VERSION 5.7 ;
  NOWIREEXTENSIONATPIN ON ;
  DIVIDERCHAR "/" ;
  BUSBITCHARS "[]" ;
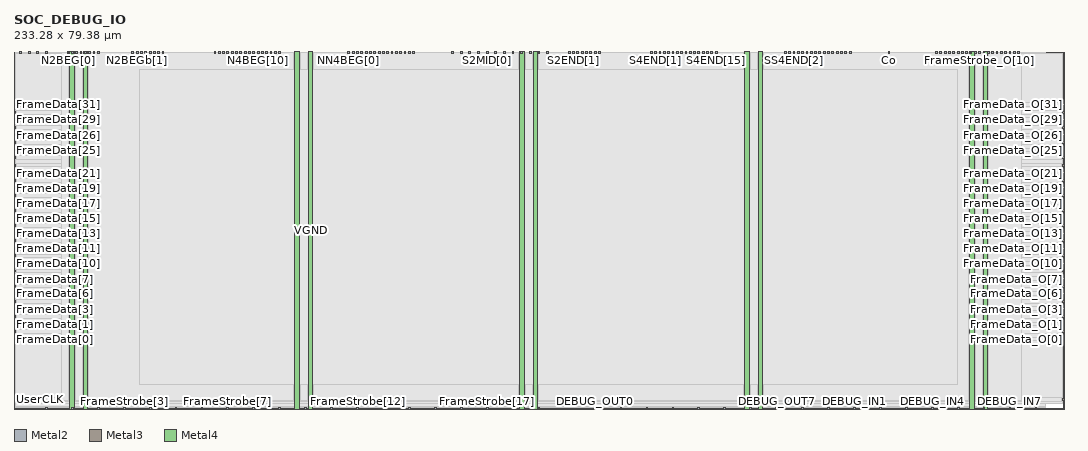
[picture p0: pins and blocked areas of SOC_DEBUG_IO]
MACRO SOC_DEBUG_IO
  CLASS BLOCK ;
  FOREIGN SOC_DEBUG_IO ;
  ORIGIN 0.000 0.000 ;
  SIZE 233.280 BY 79.380 ;
  PIN Co
    DIRECTION OUTPUT ;
    USE SIGNAL ;
    ANTENNADIFFAREA 2.314600 ;
    PORT
      LAYER Metal2 ;
        RECT 194.200 78.980 194.600 79.380 ;
    END
  END Co
  PIN DEBUG_IN0
    DIRECTION OUTPUT ;
    USE SIGNAL ;
    ANTENNADIFFAREA 2.647800 ;
    PORT
      LAYER Metal2 ;
        RECT 180.760 0.000 181.160 0.400 ;
    END
  END DEBUG_IN0
  PIN DEBUG_IN1
    DIRECTION OUTPUT ;
    USE SIGNAL ;
    ANTENNADIFFAREA 2.647800 ;
    PORT
      LAYER Metal2 ;
        RECT 186.520 0.000 186.920 0.400 ;
    END
  END DEBUG_IN1
  PIN DEBUG_IN2
    DIRECTION OUTPUT ;
    USE SIGNAL ;
    ANTENNADIFFAREA 2.647800 ;
    PORT
      LAYER Metal2 ;
        RECT 192.280 0.000 192.680 0.400 ;
    END
  END DEBUG_IN2
  PIN DEBUG_IN3
    DIRECTION OUTPUT ;
    USE SIGNAL ;
    ANTENNADIFFAREA 2.647800 ;
    PORT
      LAYER Metal2 ;
        RECT 198.040 0.000 198.440 0.400 ;
    END
  END DEBUG_IN3
  PIN DEBUG_IN4
    DIRECTION OUTPUT ;
    USE SIGNAL ;
    ANTENNADIFFAREA 2.647800 ;
    PORT
      LAYER Metal2 ;
        RECT 203.800 0.000 204.200 0.400 ;
    END
  END DEBUG_IN4
  PIN DEBUG_IN5
    DIRECTION OUTPUT ;
    USE SIGNAL ;
    ANTENNADIFFAREA 2.647800 ;
    PORT
      LAYER Metal2 ;
        RECT 209.560 0.000 209.960 0.400 ;
    END
  END DEBUG_IN5
  PIN DEBUG_IN6
    DIRECTION OUTPUT ;
    USE SIGNAL ;
    ANTENNADIFFAREA 2.647800 ;
    PORT
      LAYER Metal2 ;
        RECT 215.320 0.000 215.720 0.400 ;
    END
  END DEBUG_IN6
  PIN DEBUG_IN7
    DIRECTION OUTPUT ;
    USE SIGNAL ;
    ANTENNADIFFAREA 2.647800 ;
    PORT
      LAYER Metal2 ;
        RECT 221.080 0.000 221.480 0.400 ;
    END
  END DEBUG_IN7
  PIN DEBUG_OUT0
    DIRECTION INPUT ;
    USE SIGNAL ;
    ANTENNAGATEAREA 0.109200 ;
    PORT
      LAYER Metal2 ;
        RECT 128.920 0.000 129.320 0.400 ;
    END
  END DEBUG_OUT0
  PIN DEBUG_OUT1
    DIRECTION INPUT ;
    USE SIGNAL ;
    ANTENNAGATEAREA 0.109200 ;
    PORT
      LAYER Metal2 ;
        RECT 134.680 0.000 135.080 0.400 ;
    END
  END DEBUG_OUT1
  PIN DEBUG_OUT2
    DIRECTION INPUT ;
    USE SIGNAL ;
    ANTENNAGATEAREA 0.109200 ;
    PORT
      LAYER Metal2 ;
        RECT 140.440 0.000 140.840 0.400 ;
    END
  END DEBUG_OUT2
  PIN DEBUG_OUT3
    DIRECTION INPUT ;
    USE SIGNAL ;
    ANTENNAGATEAREA 0.109200 ;
    PORT
      LAYER Metal2 ;
        RECT 146.200 0.000 146.600 0.400 ;
    END
  END DEBUG_OUT3
  PIN DEBUG_OUT4
    DIRECTION INPUT ;
    USE SIGNAL ;
    ANTENNAGATEAREA 0.109200 ;
    PORT
      LAYER Metal2 ;
        RECT 151.960 0.000 152.360 0.400 ;
    END
  END DEBUG_OUT4
  PIN DEBUG_OUT5
    DIRECTION INPUT ;
    USE SIGNAL ;
    ANTENNAGATEAREA 0.109200 ;
    PORT
      LAYER Metal2 ;
        RECT 157.720 0.000 158.120 0.400 ;
    END
  END DEBUG_OUT5
  PIN DEBUG_OUT6
    DIRECTION INPUT ;
    USE SIGNAL ;
    ANTENNAGATEAREA 0.109200 ;
    PORT
      LAYER Metal2 ;
        RECT 163.480 0.000 163.880 0.400 ;
    END
  END DEBUG_OUT6
  PIN DEBUG_OUT7
    DIRECTION INPUT ;
    USE SIGNAL ;
    ANTENNAGATEAREA 0.109200 ;
    PORT
      LAYER Metal2 ;
        RECT 169.240 0.000 169.640 0.400 ;
    END
  END DEBUG_OUT7
  PIN FrameData[0]
    DIRECTION INPUT ;
    USE SIGNAL ;
    ANTENNAGATEAREA 0.722800 ;
    ANTENNADIFFAREA 32.246399 ;
    PORT
      LAYER Metal3 ;
        RECT 0.000 15.340 0.400 15.740 ;
    END
  END FrameData[0]
  PIN FrameData[10]
    DIRECTION INPUT ;
    USE SIGNAL ;
    ANTENNAGATEAREA 0.903500 ;
    PORT
      LAYER Metal3 ;
        RECT 0.000 32.140 0.400 32.540 ;
    END
  END FrameData[10]
  PIN FrameData[11]
    DIRECTION INPUT ;
    USE SIGNAL ;
    ANTENNAGATEAREA 0.903500 ;
    PORT
      LAYER Metal3 ;
        RECT 0.000 33.820 0.400 34.220 ;
    END
  END FrameData[11]
  PIN FrameData[12]
    DIRECTION INPUT ;
    USE SIGNAL ;
    ANTENNAGATEAREA 0.903500 ;
    PORT
      LAYER Metal3 ;
        RECT 0.000 35.500 0.400 35.900 ;
    END
  END FrameData[12]
  PIN FrameData[13]
    DIRECTION INPUT ;
    USE SIGNAL ;
    ANTENNAGATEAREA 0.903500 ;
    PORT
      LAYER Metal3 ;
        RECT 0.000 37.180 0.400 37.580 ;
    END
  END FrameData[13]
  PIN FrameData[14]
    DIRECTION INPUT ;
    USE SIGNAL ;
    ANTENNAGATEAREA 0.903500 ;
    PORT
      LAYER Metal3 ;
        RECT 0.000 38.860 0.400 39.260 ;
    END
  END FrameData[14]
  PIN FrameData[15]
    DIRECTION INPUT ;
    USE SIGNAL ;
    ANTENNAGATEAREA 0.903500 ;
    PORT
      LAYER Metal3 ;
        RECT 0.000 40.540 0.400 40.940 ;
    END
  END FrameData[15]
  PIN FrameData[16]
    DIRECTION INPUT ;
    USE SIGNAL ;
    ANTENNAGATEAREA 0.903500 ;
    PORT
      LAYER Metal3 ;
        RECT 0.000 42.220 0.400 42.620 ;
    END
  END FrameData[16]
  PIN FrameData[17]
    DIRECTION INPUT ;
    USE SIGNAL ;
    ANTENNAGATEAREA 0.903500 ;
    PORT
      LAYER Metal3 ;
        RECT 0.000 43.900 0.400 44.300 ;
    END
  END FrameData[17]
  PIN FrameData[18]
    DIRECTION INPUT ;
    USE SIGNAL ;
    ANTENNAGATEAREA 0.903500 ;
    PORT
      LAYER Metal3 ;
        RECT 0.000 45.580 0.400 45.980 ;
    END
  END FrameData[18]
  PIN FrameData[19]
    DIRECTION INPUT ;
    USE SIGNAL ;
    ANTENNAGATEAREA 0.903500 ;
    PORT
      LAYER Metal3 ;
        RECT 0.000 47.260 0.400 47.660 ;
    END
  END FrameData[19]
  PIN FrameData[1]
    DIRECTION INPUT ;
    USE SIGNAL ;
    ANTENNAGATEAREA 0.722800 ;
    ANTENNADIFFAREA 16.123199 ;
    PORT
      LAYER Metal3 ;
        RECT 0.000 17.020 0.400 17.420 ;
    END
  END FrameData[1]
  PIN FrameData[20]
    DIRECTION INPUT ;
    USE SIGNAL ;
    ANTENNAGATEAREA 0.903500 ;
    PORT
      LAYER Metal3 ;
        RECT 0.000 48.940 0.400 49.340 ;
    END
  END FrameData[20]
  PIN FrameData[21]
    DIRECTION INPUT ;
    USE SIGNAL ;
    ANTENNAGATEAREA 0.903500 ;
    PORT
      LAYER Metal3 ;
        RECT 0.000 50.620 0.400 51.020 ;
    END
  END FrameData[21]
  PIN FrameData[22]
    DIRECTION INPUT ;
    USE SIGNAL ;
    ANTENNAGATEAREA 0.903500 ;
    PORT
      LAYER Metal3 ;
        RECT 0.000 52.300 0.400 52.700 ;
    END
  END FrameData[22]
  PIN FrameData[23]
    DIRECTION INPUT ;
    USE SIGNAL ;
    ANTENNAGATEAREA 0.903500 ;
    PORT
      LAYER Metal3 ;
        RECT 0.000 53.980 0.400 54.380 ;
    END
  END FrameData[23]
  PIN FrameData[24]
    DIRECTION INPUT ;
    USE SIGNAL ;
    ANTENNAGATEAREA 0.903500 ;
    PORT
      LAYER Metal3 ;
        RECT 0.000 55.660 0.400 56.060 ;
    END
  END FrameData[24]
  PIN FrameData[25]
    DIRECTION INPUT ;
    USE SIGNAL ;
    ANTENNAGATEAREA 0.903500 ;
    PORT
      LAYER Metal3 ;
        RECT 0.000 57.340 0.400 57.740 ;
    END
  END FrameData[25]
  PIN FrameData[26]
    DIRECTION INPUT ;
    USE SIGNAL ;
    ANTENNAGATEAREA 0.903500 ;
    PORT
      LAYER Metal3 ;
        RECT 0.000 59.020 0.400 59.420 ;
    END
  END FrameData[26]
  PIN FrameData[27]
    DIRECTION INPUT ;
    USE SIGNAL ;
    ANTENNAGATEAREA 0.903500 ;
    PORT
      LAYER Metal3 ;
        RECT 0.000 60.700 0.400 61.100 ;
    END
  END FrameData[27]
  PIN FrameData[28]
    DIRECTION INPUT ;
    USE SIGNAL ;
    ANTENNAGATEAREA 0.903500 ;
    PORT
      LAYER Metal3 ;
        RECT 0.000 62.380 0.400 62.780 ;
    END
  END FrameData[28]
  PIN FrameData[29]
    DIRECTION INPUT ;
    USE SIGNAL ;
    ANTENNAGATEAREA 0.903500 ;
    PORT
      LAYER Metal3 ;
        RECT 0.000 64.060 0.400 64.460 ;
    END
  END FrameData[29]
  PIN FrameData[2]
    DIRECTION INPUT ;
    USE SIGNAL ;
    ANTENNAGATEAREA 0.722800 ;
    PORT
      LAYER Metal3 ;
        RECT 0.000 18.700 0.400 19.100 ;
    END
  END FrameData[2]
  PIN FrameData[30]
    DIRECTION INPUT ;
    USE SIGNAL ;
    ANTENNAGATEAREA 0.903500 ;
    PORT
      LAYER Metal3 ;
        RECT 0.000 65.740 0.400 66.140 ;
    END
  END FrameData[30]
  PIN FrameData[31]
    DIRECTION INPUT ;
    USE SIGNAL ;
    ANTENNAGATEAREA 0.903500 ;
    PORT
      LAYER Metal3 ;
        RECT 0.000 67.420 0.400 67.820 ;
    END
  END FrameData[31]
  PIN FrameData[3]
    DIRECTION INPUT ;
    USE SIGNAL ;
    ANTENNAGATEAREA 0.722800 ;
    PORT
      LAYER Metal3 ;
        RECT 0.000 20.380 0.400 20.780 ;
    END
  END FrameData[3]
  PIN FrameData[4]
    DIRECTION INPUT ;
    USE SIGNAL ;
    ANTENNAGATEAREA 0.722800 ;
    PORT
      LAYER Metal3 ;
        RECT 0.000 22.060 0.400 22.460 ;
    END
  END FrameData[4]
  PIN FrameData[5]
    DIRECTION INPUT ;
    USE SIGNAL ;
    ANTENNAGATEAREA 0.722800 ;
    PORT
      LAYER Metal3 ;
        RECT 0.000 23.740 0.400 24.140 ;
    END
  END FrameData[5]
  PIN FrameData[6]
    DIRECTION INPUT ;
    USE SIGNAL ;
    ANTENNAGATEAREA 0.722800 ;
    PORT
      LAYER Metal3 ;
        RECT 0.000 25.420 0.400 25.820 ;
    END
  END FrameData[6]
  PIN FrameData[7]
    DIRECTION INPUT ;
    USE SIGNAL ;
    ANTENNAGATEAREA 0.722800 ;
    PORT
      LAYER Metal3 ;
        RECT 0.000 27.100 0.400 27.500 ;
    END
  END FrameData[7]
  PIN FrameData[8]
    DIRECTION INPUT ;
    USE SIGNAL ;
    ANTENNAGATEAREA 0.722800 ;
    PORT
      LAYER Metal3 ;
        RECT 0.000 28.780 0.400 29.180 ;
    END
  END FrameData[8]
  PIN FrameData[9]
    DIRECTION INPUT ;
    USE SIGNAL ;
    ANTENNAGATEAREA 0.722800 ;
    ANTENNADIFFAREA 8.061600 ;
    PORT
      LAYER Metal3 ;
        RECT 0.000 30.460 0.400 30.860 ;
    END
  END FrameData[9]
  PIN FrameData_O[0]
    DIRECTION OUTPUT ;
    USE SIGNAL ;
    ANTENNADIFFAREA 2.724000 ;
    PORT
      LAYER Metal3 ;
        RECT 232.880 15.340 233.280 15.740 ;
    END
  END FrameData_O[0]
  PIN FrameData_O[10]
    DIRECTION OUTPUT ;
    USE SIGNAL ;
    ANTENNADIFFAREA 2.724000 ;
    PORT
      LAYER Metal3 ;
        RECT 232.880 32.140 233.280 32.540 ;
    END
  END FrameData_O[10]
  PIN FrameData_O[11]
    DIRECTION OUTPUT ;
    USE SIGNAL ;
    ANTENNADIFFAREA 2.724000 ;
    PORT
      LAYER Metal3 ;
        RECT 232.880 33.820 233.280 34.220 ;
    END
  END FrameData_O[11]
  PIN FrameData_O[12]
    DIRECTION OUTPUT ;
    USE SIGNAL ;
    ANTENNADIFFAREA 2.724000 ;
    PORT
      LAYER Metal3 ;
        RECT 232.880 35.500 233.280 35.900 ;
    END
  END FrameData_O[12]
  PIN FrameData_O[13]
    DIRECTION OUTPUT ;
    USE SIGNAL ;
    ANTENNADIFFAREA 2.724000 ;
    PORT
      LAYER Metal3 ;
        RECT 232.880 37.180 233.280 37.580 ;
    END
  END FrameData_O[13]
  PIN FrameData_O[14]
    DIRECTION OUTPUT ;
    USE SIGNAL ;
    ANTENNADIFFAREA 2.724000 ;
    PORT
      LAYER Metal3 ;
        RECT 232.880 38.860 233.280 39.260 ;
    END
  END FrameData_O[14]
  PIN FrameData_O[15]
    DIRECTION OUTPUT ;
    USE SIGNAL ;
    ANTENNADIFFAREA 2.724000 ;
    PORT
      LAYER Metal3 ;
        RECT 232.880 40.540 233.280 40.940 ;
    END
  END FrameData_O[15]
  PIN FrameData_O[16]
    DIRECTION OUTPUT ;
    USE SIGNAL ;
    ANTENNADIFFAREA 2.724000 ;
    PORT
      LAYER Metal3 ;
        RECT 232.880 42.220 233.280 42.620 ;
    END
  END FrameData_O[16]
  PIN FrameData_O[17]
    DIRECTION OUTPUT ;
    USE SIGNAL ;
    ANTENNADIFFAREA 2.724000 ;
    PORT
      LAYER Metal3 ;
        RECT 232.880 43.900 233.280 44.300 ;
    END
  END FrameData_O[17]
  PIN FrameData_O[18]
    DIRECTION OUTPUT ;
    USE SIGNAL ;
    ANTENNADIFFAREA 2.724000 ;
    PORT
      LAYER Metal3 ;
        RECT 232.880 45.580 233.280 45.980 ;
    END
  END FrameData_O[18]
  PIN FrameData_O[19]
    DIRECTION OUTPUT ;
    USE SIGNAL ;
    ANTENNADIFFAREA 2.724000 ;
    PORT
      LAYER Metal3 ;
        RECT 232.880 47.260 233.280 47.660 ;
    END
  END FrameData_O[19]
  PIN FrameData_O[1]
    DIRECTION OUTPUT ;
    USE SIGNAL ;
    ANTENNADIFFAREA 2.724000 ;
    PORT
      LAYER Metal3 ;
        RECT 232.880 17.020 233.280 17.420 ;
    END
  END FrameData_O[1]
  PIN FrameData_O[20]
    DIRECTION OUTPUT ;
    USE SIGNAL ;
    ANTENNADIFFAREA 2.724000 ;
    PORT
      LAYER Metal3 ;
        RECT 232.880 48.940 233.280 49.340 ;
    END
  END FrameData_O[20]
  PIN FrameData_O[21]
    DIRECTION OUTPUT ;
    USE SIGNAL ;
    ANTENNADIFFAREA 2.724000 ;
    PORT
      LAYER Metal3 ;
        RECT 232.880 50.620 233.280 51.020 ;
    END
  END FrameData_O[21]
  PIN FrameData_O[22]
    DIRECTION OUTPUT ;
    USE SIGNAL ;
    ANTENNADIFFAREA 2.724000 ;
    PORT
      LAYER Metal3 ;
        RECT 232.880 52.300 233.280 52.700 ;
    END
  END FrameData_O[22]
  PIN FrameData_O[23]
    DIRECTION OUTPUT ;
    USE SIGNAL ;
    ANTENNADIFFAREA 2.724000 ;
    PORT
      LAYER Metal3 ;
        RECT 232.880 53.980 233.280 54.380 ;
    END
  END FrameData_O[23]
  PIN FrameData_O[24]
    DIRECTION OUTPUT ;
    USE SIGNAL ;
    ANTENNADIFFAREA 2.724000 ;
    PORT
      LAYER Metal3 ;
        RECT 232.880 55.660 233.280 56.060 ;
    END
  END FrameData_O[24]
  PIN FrameData_O[25]
    DIRECTION OUTPUT ;
    USE SIGNAL ;
    ANTENNADIFFAREA 2.724000 ;
    PORT
      LAYER Metal3 ;
        RECT 232.880 57.340 233.280 57.740 ;
    END
  END FrameData_O[25]
  PIN FrameData_O[26]
    DIRECTION OUTPUT ;
    USE SIGNAL ;
    ANTENNADIFFAREA 2.724000 ;
    PORT
      LAYER Metal3 ;
        RECT 232.880 59.020 233.280 59.420 ;
    END
  END FrameData_O[26]
  PIN FrameData_O[27]
    DIRECTION OUTPUT ;
    USE SIGNAL ;
    ANTENNADIFFAREA 2.724000 ;
    PORT
      LAYER Metal3 ;
        RECT 232.880 60.700 233.280 61.100 ;
    END
  END FrameData_O[27]
  PIN FrameData_O[28]
    DIRECTION OUTPUT ;
    USE SIGNAL ;
    ANTENNADIFFAREA 2.724000 ;
    PORT
      LAYER Metal3 ;
        RECT 232.880 62.380 233.280 62.780 ;
    END
  END FrameData_O[28]
  PIN FrameData_O[29]
    DIRECTION OUTPUT ;
    USE SIGNAL ;
    ANTENNADIFFAREA 2.724000 ;
    PORT
      LAYER Metal3 ;
        RECT 232.880 64.060 233.280 64.460 ;
    END
  END FrameData_O[29]
  PIN FrameData_O[2]
    DIRECTION OUTPUT ;
    USE SIGNAL ;
    ANTENNADIFFAREA 2.724000 ;
    PORT
      LAYER Metal3 ;
        RECT 232.880 18.700 233.280 19.100 ;
    END
  END FrameData_O[2]
  PIN FrameData_O[30]
    DIRECTION OUTPUT ;
    USE SIGNAL ;
    ANTENNADIFFAREA 2.724000 ;
    PORT
      LAYER Metal3 ;
        RECT 232.880 65.740 233.280 66.140 ;
    END
  END FrameData_O[30]
  PIN FrameData_O[31]
    DIRECTION OUTPUT ;
    USE SIGNAL ;
    ANTENNADIFFAREA 2.724000 ;
    PORT
      LAYER Metal3 ;
        RECT 232.880 67.420 233.280 67.820 ;
    END
  END FrameData_O[31]
  PIN FrameData_O[3]
    DIRECTION OUTPUT ;
    USE SIGNAL ;
    ANTENNADIFFAREA 2.724000 ;
    PORT
      LAYER Metal3 ;
        RECT 232.880 20.380 233.280 20.780 ;
    END
  END FrameData_O[3]
  PIN FrameData_O[4]
    DIRECTION OUTPUT ;
    USE SIGNAL ;
    ANTENNADIFFAREA 2.724000 ;
    PORT
      LAYER Metal3 ;
        RECT 232.880 22.060 233.280 22.460 ;
    END
  END FrameData_O[4]
  PIN FrameData_O[5]
    DIRECTION OUTPUT ;
    USE SIGNAL ;
    ANTENNADIFFAREA 2.724000 ;
    PORT
      LAYER Metal3 ;
        RECT 232.880 23.740 233.280 24.140 ;
    END
  END FrameData_O[5]
  PIN FrameData_O[6]
    DIRECTION OUTPUT ;
    USE SIGNAL ;
    ANTENNADIFFAREA 2.724000 ;
    PORT
      LAYER Metal3 ;
        RECT 232.880 25.420 233.280 25.820 ;
    END
  END FrameData_O[6]
  PIN FrameData_O[7]
    DIRECTION OUTPUT ;
    USE SIGNAL ;
    ANTENNADIFFAREA 2.724000 ;
    PORT
      LAYER Metal3 ;
        RECT 232.880 27.100 233.280 27.500 ;
    END
  END FrameData_O[7]
  PIN FrameData_O[8]
    DIRECTION OUTPUT ;
    USE SIGNAL ;
    ANTENNADIFFAREA 2.724000 ;
    PORT
      LAYER Metal3 ;
        RECT 232.880 28.780 233.280 29.180 ;
    END
  END FrameData_O[8]
  PIN FrameData_O[9]
    DIRECTION OUTPUT ;
    USE SIGNAL ;
    ANTENNADIFFAREA 2.724000 ;
    PORT
      LAYER Metal3 ;
        RECT 232.880 30.460 233.280 30.860 ;
    END
  END FrameData_O[9]
  PIN FrameStrobe[0]
    DIRECTION INPUT ;
    USE SIGNAL ;
    ANTENNAGATEAREA 11.745500 ;
    PORT
      LAYER Metal2 ;
        RECT 7.000 0.000 7.400 0.400 ;
    END
  END FrameStrobe[0]
  PIN FrameStrobe[10]
    DIRECTION INPUT ;
    USE SIGNAL ;
    ANTENNAGATEAREA 0.180700 ;
    PORT
      LAYER Metal2 ;
        RECT 64.600 0.000 65.000 0.400 ;
    END
  END FrameStrobe[10]
  PIN FrameStrobe[11]
    DIRECTION INPUT ;
    USE SIGNAL ;
    ANTENNAGATEAREA 0.180700 ;
    PORT
      LAYER Metal2 ;
        RECT 70.360 0.000 70.760 0.400 ;
    END
  END FrameStrobe[11]
  PIN FrameStrobe[12]
    DIRECTION INPUT ;
    USE SIGNAL ;
    ANTENNAGATEAREA 0.180700 ;
    PORT
      LAYER Metal2 ;
        RECT 76.120 0.000 76.520 0.400 ;
    END
  END FrameStrobe[12]
  PIN FrameStrobe[13]
    DIRECTION INPUT ;
    USE SIGNAL ;
    ANTENNAGATEAREA 0.180700 ;
    PORT
      LAYER Metal2 ;
        RECT 81.880 0.000 82.280 0.400 ;
    END
  END FrameStrobe[13]
  PIN FrameStrobe[14]
    DIRECTION INPUT ;
    USE SIGNAL ;
    ANTENNAGATEAREA 0.180700 ;
    PORT
      LAYER Metal2 ;
        RECT 87.640 0.000 88.040 0.400 ;
    END
  END FrameStrobe[14]
  PIN FrameStrobe[15]
    DIRECTION INPUT ;
    USE SIGNAL ;
    ANTENNAGATEAREA 0.180700 ;
    PORT
      LAYER Metal2 ;
        RECT 93.400 0.000 93.800 0.400 ;
    END
  END FrameStrobe[15]
  PIN FrameStrobe[16]
    DIRECTION INPUT ;
    USE SIGNAL ;
    ANTENNAGATEAREA 0.180700 ;
    PORT
      LAYER Metal2 ;
        RECT 99.160 0.000 99.560 0.400 ;
    END
  END FrameStrobe[16]
  PIN FrameStrobe[17]
    DIRECTION INPUT ;
    USE SIGNAL ;
    ANTENNAGATEAREA 0.180700 ;
    PORT
      LAYER Metal2 ;
        RECT 104.920 0.000 105.320 0.400 ;
    END
  END FrameStrobe[17]
  PIN FrameStrobe[18]
    DIRECTION INPUT ;
    USE SIGNAL ;
    ANTENNAGATEAREA 0.180700 ;
    PORT
      LAYER Metal2 ;
        RECT 110.680 0.000 111.080 0.400 ;
    END
  END FrameStrobe[18]
  PIN FrameStrobe[19]
    DIRECTION INPUT ;
    USE SIGNAL ;
    ANTENNAGATEAREA 0.180700 ;
    PORT
      LAYER Metal2 ;
        RECT 116.440 0.000 116.840 0.400 ;
    END
  END FrameStrobe[19]
  PIN FrameStrobe[1]
    DIRECTION INPUT ;
    USE SIGNAL ;
    ANTENNAGATEAREA 11.745500 ;
    PORT
      LAYER Metal2 ;
        RECT 12.760 0.000 13.160 0.400 ;
    END
  END FrameStrobe[1]
  PIN FrameStrobe[2]
    DIRECTION INPUT ;
    USE SIGNAL ;
    ANTENNAGATEAREA 11.745500 ;
    PORT
      LAYER Metal2 ;
        RECT 18.520 0.000 18.920 0.400 ;
    END
  END FrameStrobe[2]
  PIN FrameStrobe[3]
    DIRECTION INPUT ;
    USE SIGNAL ;
    ANTENNAGATEAREA 8.131500 ;
    PORT
      LAYER Metal2 ;
        RECT 24.280 0.000 24.680 0.400 ;
    END
  END FrameStrobe[3]
  PIN FrameStrobe[4]
    DIRECTION INPUT ;
    USE SIGNAL ;
    ANTENNAGATEAREA 0.180700 ;
    PORT
      LAYER Metal2 ;
        RECT 30.040 0.000 30.440 0.400 ;
    END
  END FrameStrobe[4]
  PIN FrameStrobe[5]
    DIRECTION INPUT ;
    USE SIGNAL ;
    ANTENNAGATEAREA 0.180700 ;
    PORT
      LAYER Metal2 ;
        RECT 35.800 0.000 36.200 0.400 ;
    END
  END FrameStrobe[5]
  PIN FrameStrobe[6]
    DIRECTION INPUT ;
    USE SIGNAL ;
    ANTENNAGATEAREA 0.180700 ;
    PORT
      LAYER Metal2 ;
        RECT 41.560 0.000 41.960 0.400 ;
    END
  END FrameStrobe[6]
  PIN FrameStrobe[7]
    DIRECTION INPUT ;
    USE SIGNAL ;
    ANTENNAGATEAREA 0.180700 ;
    PORT
      LAYER Metal2 ;
        RECT 47.320 0.000 47.720 0.400 ;
    END
  END FrameStrobe[7]
  PIN FrameStrobe[8]
    DIRECTION INPUT ;
    USE SIGNAL ;
    ANTENNAGATEAREA 0.180700 ;
    PORT
      LAYER Metal2 ;
        RECT 53.080 0.000 53.480 0.400 ;
    END
  END FrameStrobe[8]
  PIN FrameStrobe[9]
    DIRECTION INPUT ;
    USE SIGNAL ;
    ANTENNAGATEAREA 0.180700 ;
    PORT
      LAYER Metal2 ;
        RECT 58.840 0.000 59.240 0.400 ;
    END
  END FrameStrobe[9]
  PIN FrameStrobe_O[0]
    DIRECTION OUTPUT ;
    USE SIGNAL ;
    ANTENNADIFFAREA 2.724000 ;
    PORT
      LAYER Metal2 ;
        RECT 204.760 78.980 205.160 79.380 ;
    END
  END FrameStrobe_O[0]
  PIN FrameStrobe_O[10]
    DIRECTION OUTPUT ;
    USE SIGNAL ;
    ANTENNADIFFAREA 2.724000 ;
    PORT
      LAYER Metal2 ;
        RECT 214.360 78.980 214.760 79.380 ;
    END
  END FrameStrobe_O[10]
  PIN FrameStrobe_O[11]
    DIRECTION OUTPUT ;
    USE SIGNAL ;
    ANTENNADIFFAREA 2.724000 ;
    PORT
      LAYER Metal2 ;
        RECT 215.320 78.980 215.720 79.380 ;
    END
  END FrameStrobe_O[11]
  PIN FrameStrobe_O[12]
    DIRECTION OUTPUT ;
    USE SIGNAL ;
    ANTENNADIFFAREA 2.724000 ;
    PORT
      LAYER Metal2 ;
        RECT 216.280 78.980 216.680 79.380 ;
    END
  END FrameStrobe_O[12]
  PIN FrameStrobe_O[13]
    DIRECTION OUTPUT ;
    USE SIGNAL ;
    ANTENNADIFFAREA 2.724000 ;
    PORT
      LAYER Metal2 ;
        RECT 217.240 78.980 217.640 79.380 ;
    END
  END FrameStrobe_O[13]
  PIN FrameStrobe_O[14]
    DIRECTION OUTPUT ;
    USE SIGNAL ;
    ANTENNADIFFAREA 2.724000 ;
    PORT
      LAYER Metal2 ;
        RECT 218.200 78.980 218.600 79.380 ;
    END
  END FrameStrobe_O[14]
  PIN FrameStrobe_O[15]
    DIRECTION OUTPUT ;
    USE SIGNAL ;
    ANTENNADIFFAREA 2.724000 ;
    PORT
      LAYER Metal2 ;
        RECT 219.160 78.980 219.560 79.380 ;
    END
  END FrameStrobe_O[15]
  PIN FrameStrobe_O[16]
    DIRECTION OUTPUT ;
    USE SIGNAL ;
    ANTENNADIFFAREA 2.724000 ;
    PORT
      LAYER Metal2 ;
        RECT 220.120 78.980 220.520 79.380 ;
    END
  END FrameStrobe_O[16]
  PIN FrameStrobe_O[17]
    DIRECTION OUTPUT ;
    USE SIGNAL ;
    ANTENNADIFFAREA 2.724000 ;
    PORT
      LAYER Metal2 ;
        RECT 221.080 78.980 221.480 79.380 ;
    END
  END FrameStrobe_O[17]
  PIN FrameStrobe_O[18]
    DIRECTION OUTPUT ;
    USE SIGNAL ;
    ANTENNADIFFAREA 2.724000 ;
    PORT
      LAYER Metal2 ;
        RECT 222.040 78.980 222.440 79.380 ;
    END
  END FrameStrobe_O[18]
  PIN FrameStrobe_O[19]
    DIRECTION OUTPUT ;
    USE SIGNAL ;
    ANTENNADIFFAREA 2.724000 ;
    PORT
      LAYER Metal2 ;
        RECT 223.000 78.980 223.400 79.380 ;
    END
  END FrameStrobe_O[19]
  PIN FrameStrobe_O[1]
    DIRECTION OUTPUT ;
    USE SIGNAL ;
    ANTENNADIFFAREA 2.724000 ;
    PORT
      LAYER Metal2 ;
        RECT 205.720 78.980 206.120 79.380 ;
    END
  END FrameStrobe_O[1]
  PIN FrameStrobe_O[2]
    DIRECTION OUTPUT ;
    USE SIGNAL ;
    ANTENNADIFFAREA 2.724000 ;
    PORT
      LAYER Metal2 ;
        RECT 206.680 78.980 207.080 79.380 ;
    END
  END FrameStrobe_O[2]
  PIN FrameStrobe_O[3]
    DIRECTION OUTPUT ;
    USE SIGNAL ;
    ANTENNADIFFAREA 2.724000 ;
    PORT
      LAYER Metal2 ;
        RECT 207.640 78.980 208.040 79.380 ;
    END
  END FrameStrobe_O[3]
  PIN FrameStrobe_O[4]
    DIRECTION OUTPUT ;
    USE SIGNAL ;
    ANTENNADIFFAREA 2.724000 ;
    PORT
      LAYER Metal2 ;
        RECT 208.600 78.980 209.000 79.380 ;
    END
  END FrameStrobe_O[4]
  PIN FrameStrobe_O[5]
    DIRECTION OUTPUT ;
    USE SIGNAL ;
    ANTENNADIFFAREA 2.724000 ;
    PORT
      LAYER Metal2 ;
        RECT 209.560 78.980 209.960 79.380 ;
    END
  END FrameStrobe_O[5]
  PIN FrameStrobe_O[6]
    DIRECTION OUTPUT ;
    USE SIGNAL ;
    ANTENNADIFFAREA 2.724000 ;
    PORT
      LAYER Metal2 ;
        RECT 210.520 78.980 210.920 79.380 ;
    END
  END FrameStrobe_O[6]
  PIN FrameStrobe_O[7]
    DIRECTION OUTPUT ;
    USE SIGNAL ;
    ANTENNADIFFAREA 2.724000 ;
    PORT
      LAYER Metal2 ;
        RECT 211.480 78.980 211.880 79.380 ;
    END
  END FrameStrobe_O[7]
  PIN FrameStrobe_O[8]
    DIRECTION OUTPUT ;
    USE SIGNAL ;
    ANTENNADIFFAREA 2.724000 ;
    PORT
      LAYER Metal2 ;
        RECT 212.440 78.980 212.840 79.380 ;
    END
  END FrameStrobe_O[8]
  PIN FrameStrobe_O[9]
    DIRECTION OUTPUT ;
    USE SIGNAL ;
    ANTENNADIFFAREA 2.724000 ;
    PORT
      LAYER Metal2 ;
        RECT 213.400 78.980 213.800 79.380 ;
    END
  END FrameStrobe_O[9]
  PIN N1BEG[0]
    DIRECTION OUTPUT ;
    USE SIGNAL ;
    ANTENNADIFFAREA 2.724000 ;
    PORT
      LAYER Metal2 ;
        RECT 1.240 78.980 1.640 79.380 ;
    END
  END N1BEG[0]
  PIN N1BEG[1]
    DIRECTION OUTPUT ;
    USE SIGNAL ;
    ANTENNADIFFAREA 2.724000 ;
    PORT
      LAYER Metal2 ;
        RECT 3.160 78.980 3.560 79.380 ;
    END
  END N1BEG[1]
  PIN N1BEG[2]
    DIRECTION OUTPUT ;
    USE SIGNAL ;
    ANTENNADIFFAREA 2.724000 ;
    PORT
      LAYER Metal2 ;
        RECT 5.080 78.980 5.480 79.380 ;
    END
  END N1BEG[2]
  PIN N1BEG[3]
    DIRECTION OUTPUT ;
    USE SIGNAL ;
    ANTENNADIFFAREA 2.724000 ;
    PORT
      LAYER Metal2 ;
        RECT 7.000 78.980 7.400 79.380 ;
    END
  END N1BEG[3]
  PIN N2BEG[0]
    DIRECTION OUTPUT ;
    USE SIGNAL ;
    ANTENNADIFFAREA 2.724000 ;
    PORT
      LAYER Metal2 ;
        RECT 11.800 78.980 12.200 79.380 ;
    END
  END N2BEG[0]
  PIN N2BEG[1]
    DIRECTION OUTPUT ;
    USE SIGNAL ;
    ANTENNADIFFAREA 2.724000 ;
    PORT
      LAYER Metal2 ;
        RECT 12.760 78.980 13.160 79.380 ;
    END
  END N2BEG[1]
  PIN N2BEG[2]
    DIRECTION OUTPUT ;
    USE SIGNAL ;
    ANTENNADIFFAREA 2.724000 ;
    PORT
      LAYER Metal2 ;
        RECT 13.720 78.980 14.120 79.380 ;
    END
  END N2BEG[2]
  PIN N2BEG[3]
    DIRECTION OUTPUT ;
    USE SIGNAL ;
    ANTENNADIFFAREA 2.724000 ;
    PORT
      LAYER Metal2 ;
        RECT 14.680 78.980 15.080 79.380 ;
    END
  END N2BEG[3]
  PIN N2BEG[4]
    DIRECTION OUTPUT ;
    USE SIGNAL ;
    ANTENNADIFFAREA 2.724000 ;
    PORT
      LAYER Metal2 ;
        RECT 15.640 78.980 16.040 79.380 ;
    END
  END N2BEG[4]
  PIN N2BEG[5]
    DIRECTION OUTPUT ;
    USE SIGNAL ;
    ANTENNADIFFAREA 2.724000 ;
    PORT
      LAYER Metal2 ;
        RECT 16.600 78.980 17.000 79.380 ;
    END
  END N2BEG[5]
  PIN N2BEG[6]
    DIRECTION OUTPUT ;
    USE SIGNAL ;
    ANTENNADIFFAREA 2.724000 ;
    PORT
      LAYER Metal2 ;
        RECT 17.560 78.980 17.960 79.380 ;
    END
  END N2BEG[6]
  PIN N2BEG[7]
    DIRECTION OUTPUT ;
    USE SIGNAL ;
    ANTENNADIFFAREA 2.724000 ;
    PORT
      LAYER Metal2 ;
        RECT 18.520 78.980 18.920 79.380 ;
    END
  END N2BEG[7]
  PIN N2BEGb[0]
    DIRECTION OUTPUT ;
    USE SIGNAL ;
    ANTENNADIFFAREA 2.724000 ;
    PORT
      LAYER Metal2 ;
        RECT 26.200 78.980 26.600 79.380 ;
    END
  END N2BEGb[0]
  PIN N2BEGb[1]
    DIRECTION OUTPUT ;
    USE SIGNAL ;
    ANTENNADIFFAREA 2.724000 ;
    PORT
      LAYER Metal2 ;
        RECT 27.160 78.980 27.560 79.380 ;
    END
  END N2BEGb[1]
  PIN N2BEGb[2]
    DIRECTION OUTPUT ;
    USE SIGNAL ;
    ANTENNADIFFAREA 2.724000 ;
    PORT
      LAYER Metal2 ;
        RECT 28.120 78.980 28.520 79.380 ;
    END
  END N2BEGb[2]
  PIN N2BEGb[3]
    DIRECTION OUTPUT ;
    USE SIGNAL ;
    ANTENNADIFFAREA 2.724000 ;
    PORT
      LAYER Metal2 ;
        RECT 29.080 78.980 29.480 79.380 ;
    END
  END N2BEGb[3]
  PIN N2BEGb[4]
    DIRECTION OUTPUT ;
    USE SIGNAL ;
    ANTENNADIFFAREA 2.724000 ;
    PORT
      LAYER Metal2 ;
        RECT 30.040 78.980 30.440 79.380 ;
    END
  END N2BEGb[4]
  PIN N2BEGb[5]
    DIRECTION OUTPUT ;
    USE SIGNAL ;
    ANTENNADIFFAREA 2.724000 ;
    PORT
      LAYER Metal2 ;
        RECT 31.000 78.980 31.400 79.380 ;
    END
  END N2BEGb[5]
  PIN N2BEGb[6]
    DIRECTION OUTPUT ;
    USE SIGNAL ;
    ANTENNADIFFAREA 2.724000 ;
    PORT
      LAYER Metal2 ;
        RECT 31.960 78.980 32.360 79.380 ;
    END
  END N2BEGb[6]
  PIN N2BEGb[7]
    DIRECTION OUTPUT ;
    USE SIGNAL ;
    ANTENNADIFFAREA 2.724000 ;
    PORT
      LAYER Metal2 ;
        RECT 32.920 78.980 33.320 79.380 ;
    END
  END N2BEGb[7]
  PIN N4BEG[0]
    DIRECTION OUTPUT ;
    USE SIGNAL ;
    ANTENNADIFFAREA 2.724000 ;
    PORT
      LAYER Metal2 ;
        RECT 44.440 78.980 44.840 79.380 ;
    END
  END N4BEG[0]
  PIN N4BEG[10]
    DIRECTION OUTPUT ;
    USE SIGNAL ;
    ANTENNADIFFAREA 2.724000 ;
    PORT
      LAYER Metal2 ;
        RECT 54.040 78.980 54.440 79.380 ;
    END
  END N4BEG[10]
  PIN N4BEG[11]
    DIRECTION OUTPUT ;
    USE SIGNAL ;
    ANTENNADIFFAREA 2.724000 ;
    PORT
      LAYER Metal2 ;
        RECT 55.000 78.980 55.400 79.380 ;
    END
  END N4BEG[11]
  PIN N4BEG[12]
    DIRECTION OUTPUT ;
    USE SIGNAL ;
    ANTENNADIFFAREA 2.724000 ;
    PORT
      LAYER Metal2 ;
        RECT 55.960 78.980 56.360 79.380 ;
    END
  END N4BEG[12]
  PIN N4BEG[13]
    DIRECTION OUTPUT ;
    USE SIGNAL ;
    ANTENNADIFFAREA 2.724000 ;
    PORT
      LAYER Metal2 ;
        RECT 56.920 78.980 57.320 79.380 ;
    END
  END N4BEG[13]
  PIN N4BEG[14]
    DIRECTION OUTPUT ;
    USE SIGNAL ;
    ANTENNADIFFAREA 2.724000 ;
    PORT
      LAYER Metal2 ;
        RECT 57.880 78.980 58.280 79.380 ;
    END
  END N4BEG[14]
  PIN N4BEG[15]
    DIRECTION OUTPUT ;
    USE SIGNAL ;
    ANTENNADIFFAREA 2.724000 ;
    PORT
      LAYER Metal2 ;
        RECT 58.840 78.980 59.240 79.380 ;
    END
  END N4BEG[15]
  PIN N4BEG[1]
    DIRECTION OUTPUT ;
    USE SIGNAL ;
    ANTENNADIFFAREA 2.724000 ;
    PORT
      LAYER Metal2 ;
        RECT 45.400 78.980 45.800 79.380 ;
    END
  END N4BEG[1]
  PIN N4BEG[2]
    DIRECTION OUTPUT ;
    USE SIGNAL ;
    ANTENNADIFFAREA 2.724000 ;
    PORT
      LAYER Metal2 ;
        RECT 46.360 78.980 46.760 79.380 ;
    END
  END N4BEG[2]
  PIN N4BEG[3]
    DIRECTION OUTPUT ;
    USE SIGNAL ;
    ANTENNADIFFAREA 2.724000 ;
    PORT
      LAYER Metal2 ;
        RECT 47.320 78.980 47.720 79.380 ;
    END
  END N4BEG[3]
  PIN N4BEG[4]
    DIRECTION OUTPUT ;
    USE SIGNAL ;
    ANTENNADIFFAREA 2.724000 ;
    PORT
      LAYER Metal2 ;
        RECT 48.280 78.980 48.680 79.380 ;
    END
  END N4BEG[4]
  PIN N4BEG[5]
    DIRECTION OUTPUT ;
    USE SIGNAL ;
    ANTENNADIFFAREA 2.724000 ;
    PORT
      LAYER Metal2 ;
        RECT 49.240 78.980 49.640 79.380 ;
    END
  END N4BEG[5]
  PIN N4BEG[6]
    DIRECTION OUTPUT ;
    USE SIGNAL ;
    ANTENNADIFFAREA 2.724000 ;
    PORT
      LAYER Metal2 ;
        RECT 50.200 78.980 50.600 79.380 ;
    END
  END N4BEG[6]
  PIN N4BEG[7]
    DIRECTION OUTPUT ;
    USE SIGNAL ;
    ANTENNADIFFAREA 2.724000 ;
    PORT
      LAYER Metal2 ;
        RECT 51.160 78.980 51.560 79.380 ;
    END
  END N4BEG[7]
  PIN N4BEG[8]
    DIRECTION OUTPUT ;
    USE SIGNAL ;
    ANTENNADIFFAREA 2.724000 ;
    PORT
      LAYER Metal2 ;
        RECT 52.120 78.980 52.520 79.380 ;
    END
  END N4BEG[8]
  PIN N4BEG[9]
    DIRECTION OUTPUT ;
    USE SIGNAL ;
    ANTENNADIFFAREA 2.724000 ;
    PORT
      LAYER Metal2 ;
        RECT 53.080 78.980 53.480 79.380 ;
    END
  END N4BEG[9]
  PIN NN4BEG[0]
    DIRECTION OUTPUT ;
    USE SIGNAL ;
    ANTENNADIFFAREA 2.724000 ;
    PORT
      LAYER Metal2 ;
        RECT 74.200 78.980 74.600 79.380 ;
    END
  END NN4BEG[0]
  PIN NN4BEG[10]
    DIRECTION OUTPUT ;
    USE SIGNAL ;
    ANTENNADIFFAREA 2.724000 ;
    PORT
      LAYER Metal2 ;
        RECT 83.800 78.980 84.200 79.380 ;
    END
  END NN4BEG[10]
  PIN NN4BEG[11]
    DIRECTION OUTPUT ;
    USE SIGNAL ;
    ANTENNADIFFAREA 2.724000 ;
    PORT
      LAYER Metal2 ;
        RECT 84.760 78.980 85.160 79.380 ;
    END
  END NN4BEG[11]
  PIN NN4BEG[12]
    DIRECTION OUTPUT ;
    USE SIGNAL ;
    ANTENNADIFFAREA 2.724000 ;
    PORT
      LAYER Metal2 ;
        RECT 85.720 78.980 86.120 79.380 ;
    END
  END NN4BEG[12]
  PIN NN4BEG[13]
    DIRECTION OUTPUT ;
    USE SIGNAL ;
    ANTENNADIFFAREA 2.724000 ;
    PORT
      LAYER Metal2 ;
        RECT 86.680 78.980 87.080 79.380 ;
    END
  END NN4BEG[13]
  PIN NN4BEG[14]
    DIRECTION OUTPUT ;
    USE SIGNAL ;
    ANTENNADIFFAREA 2.724000 ;
    PORT
      LAYER Metal2 ;
        RECT 87.640 78.980 88.040 79.380 ;
    END
  END NN4BEG[14]
  PIN NN4BEG[15]
    DIRECTION OUTPUT ;
    USE SIGNAL ;
    ANTENNADIFFAREA 2.724000 ;
    PORT
      LAYER Metal2 ;
        RECT 88.600 78.980 89.000 79.380 ;
    END
  END NN4BEG[15]
  PIN NN4BEG[1]
    DIRECTION OUTPUT ;
    USE SIGNAL ;
    ANTENNADIFFAREA 2.724000 ;
    PORT
      LAYER Metal2 ;
        RECT 75.160 78.980 75.560 79.380 ;
    END
  END NN4BEG[1]
  PIN NN4BEG[2]
    DIRECTION OUTPUT ;
    USE SIGNAL ;
    ANTENNADIFFAREA 2.724000 ;
    PORT
      LAYER Metal2 ;
        RECT 76.120 78.980 76.520 79.380 ;
    END
  END NN4BEG[2]
  PIN NN4BEG[3]
    DIRECTION OUTPUT ;
    USE SIGNAL ;
    ANTENNADIFFAREA 2.724000 ;
    PORT
      LAYER Metal2 ;
        RECT 77.080 78.980 77.480 79.380 ;
    END
  END NN4BEG[3]
  PIN NN4BEG[4]
    DIRECTION OUTPUT ;
    USE SIGNAL ;
    ANTENNADIFFAREA 2.724000 ;
    PORT
      LAYER Metal2 ;
        RECT 78.040 78.980 78.440 79.380 ;
    END
  END NN4BEG[4]
  PIN NN4BEG[5]
    DIRECTION OUTPUT ;
    USE SIGNAL ;
    ANTENNADIFFAREA 2.724000 ;
    PORT
      LAYER Metal2 ;
        RECT 79.000 78.980 79.400 79.380 ;
    END
  END NN4BEG[5]
  PIN NN4BEG[6]
    DIRECTION OUTPUT ;
    USE SIGNAL ;
    ANTENNADIFFAREA 2.724000 ;
    PORT
      LAYER Metal2 ;
        RECT 79.960 78.980 80.360 79.380 ;
    END
  END NN4BEG[6]
  PIN NN4BEG[7]
    DIRECTION OUTPUT ;
    USE SIGNAL ;
    ANTENNADIFFAREA 2.724000 ;
    PORT
      LAYER Metal2 ;
        RECT 80.920 78.980 81.320 79.380 ;
    END
  END NN4BEG[7]
  PIN NN4BEG[8]
    DIRECTION OUTPUT ;
    USE SIGNAL ;
    ANTENNADIFFAREA 2.724000 ;
    PORT
      LAYER Metal2 ;
        RECT 81.880 78.980 82.280 79.380 ;
    END
  END NN4BEG[8]
  PIN NN4BEG[9]
    DIRECTION OUTPUT ;
    USE SIGNAL ;
    ANTENNADIFFAREA 2.724000 ;
    PORT
      LAYER Metal2 ;
        RECT 82.840 78.980 83.240 79.380 ;
    END
  END NN4BEG[9]
  PIN S1END[0]
    DIRECTION INPUT ;
    USE SIGNAL ;
    ANTENNAGATEAREA 0.852800 ;
    PORT
      LAYER Metal2 ;
        RECT 97.240 78.980 97.640 79.380 ;
    END
  END S1END[0]
  PIN S1END[1]
    DIRECTION INPUT ;
    USE SIGNAL ;
    ANTENNAGATEAREA 0.852800 ;
    PORT
      LAYER Metal2 ;
        RECT 99.160 78.980 99.560 79.380 ;
    END
  END S1END[1]
  PIN S1END[2]
    DIRECTION INPUT ;
    USE SIGNAL ;
    ANTENNAGATEAREA 0.639600 ;
    PORT
      LAYER Metal2 ;
        RECT 101.080 78.980 101.480 79.380 ;
    END
  END S1END[2]
  PIN S1END[3]
    DIRECTION INPUT ;
    USE SIGNAL ;
    ANTENNAGATEAREA 0.639600 ;
    PORT
      LAYER Metal2 ;
        RECT 103.000 78.980 103.400 79.380 ;
    END
  END S1END[3]
  PIN S2END[0]
    DIRECTION INPUT ;
    USE SIGNAL ;
    ANTENNAGATEAREA 1.066000 ;
    PORT
      LAYER Metal2 ;
        RECT 123.160 78.980 123.560 79.380 ;
    END
  END S2END[0]
  PIN S2END[1]
    DIRECTION INPUT ;
    USE SIGNAL ;
    ANTENNAGATEAREA 0.852800 ;
    PORT
      LAYER Metal2 ;
        RECT 124.120 78.980 124.520 79.380 ;
    END
  END S2END[1]
  PIN S2END[2]
    DIRECTION INPUT ;
    USE SIGNAL ;
    ANTENNAGATEAREA 1.066000 ;
    PORT
      LAYER Metal2 ;
        RECT 125.080 78.980 125.480 79.380 ;
    END
  END S2END[2]
  PIN S2END[3]
    DIRECTION INPUT ;
    USE SIGNAL ;
    ANTENNAGATEAREA 0.852800 ;
    PORT
      LAYER Metal2 ;
        RECT 126.040 78.980 126.440 79.380 ;
    END
  END S2END[3]
  PIN S2END[4]
    DIRECTION INPUT ;
    USE SIGNAL ;
    ANTENNAGATEAREA 1.066000 ;
    PORT
      LAYER Metal2 ;
        RECT 127.000 78.980 127.400 79.380 ;
    END
  END S2END[4]
  PIN S2END[5]
    DIRECTION INPUT ;
    USE SIGNAL ;
    ANTENNAGATEAREA 0.852800 ;
    PORT
      LAYER Metal2 ;
        RECT 127.960 78.980 128.360 79.380 ;
    END
  END S2END[5]
  PIN S2END[6]
    DIRECTION INPUT ;
    USE SIGNAL ;
    ANTENNAGATEAREA 1.066000 ;
    PORT
      LAYER Metal2 ;
        RECT 128.920 78.980 129.320 79.380 ;
    END
  END S2END[6]
  PIN S2END[7]
    DIRECTION INPUT ;
    USE SIGNAL ;
    ANTENNAGATEAREA 0.852800 ;
    PORT
      LAYER Metal2 ;
        RECT 129.880 78.980 130.280 79.380 ;
    END
  END S2END[7]
  PIN S2MID[0]
    DIRECTION INPUT ;
    USE SIGNAL ;
    ANTENNAGATEAREA 1.246700 ;
    PORT
      LAYER Metal2 ;
        RECT 104.920 78.980 105.320 79.380 ;
    END
  END S2MID[0]
  PIN S2MID[1]
    DIRECTION INPUT ;
    USE SIGNAL ;
    ANTENNAGATEAREA 1.279200 ;
    PORT
      LAYER Metal2 ;
        RECT 106.840 78.980 107.240 79.380 ;
    END
  END S2MID[1]
  PIN S2MID[2]
    DIRECTION INPUT ;
    USE SIGNAL ;
    ANTENNAGATEAREA 1.246700 ;
    PORT
      LAYER Metal2 ;
        RECT 108.760 78.980 109.160 79.380 ;
    END
  END S2MID[2]
  PIN S2MID[3]
    DIRECTION INPUT ;
    USE SIGNAL ;
    ANTENNAGATEAREA 1.279200 ;
    PORT
      LAYER Metal2 ;
        RECT 110.680 78.980 111.080 79.380 ;
    END
  END S2MID[3]
  PIN S2MID[4]
    DIRECTION INPUT ;
    USE SIGNAL ;
    ANTENNAGATEAREA 1.033500 ;
    PORT
      LAYER Metal2 ;
        RECT 112.600 78.980 113.000 79.380 ;
    END
  END S2MID[4]
  PIN S2MID[5]
    DIRECTION INPUT ;
    USE SIGNAL ;
    ANTENNAGATEAREA 1.066000 ;
    PORT
      LAYER Metal2 ;
        RECT 114.520 78.980 114.920 79.380 ;
    END
  END S2MID[5]
  PIN S2MID[6]
    DIRECTION INPUT ;
    USE SIGNAL ;
    ANTENNAGATEAREA 1.033500 ;
    PORT
      LAYER Metal2 ;
        RECT 116.440 78.980 116.840 79.380 ;
    END
  END S2MID[6]
  PIN S2MID[7]
    DIRECTION INPUT ;
    USE SIGNAL ;
    ANTENNAGATEAREA 1.066000 ;
    PORT
      LAYER Metal2 ;
        RECT 118.360 78.980 118.760 79.380 ;
    END
  END S2MID[7]
  PIN S4END[0]
    DIRECTION INPUT ;
    USE SIGNAL ;
    ANTENNAGATEAREA 0.426400 ;
    PORT
      LAYER Metal2 ;
        RECT 141.400 78.980 141.800 79.380 ;
    END
  END S4END[0]
  PIN S4END[10]
    DIRECTION INPUT ;
    USE SIGNAL ;
    ANTENNAGATEAREA 0.639600 ;
    PORT
      LAYER Metal2 ;
        RECT 151.000 78.980 151.400 79.380 ;
    END
  END S4END[10]
  PIN S4END[11]
    DIRECTION INPUT ;
    USE SIGNAL ;
    ANTENNAGATEAREA 0.639600 ;
    PORT
      LAYER Metal2 ;
        RECT 151.960 78.980 152.360 79.380 ;
    END
  END S4END[11]
  PIN S4END[12]
    DIRECTION INPUT ;
    USE SIGNAL ;
    ANTENNAGATEAREA 0.852800 ;
    PORT
      LAYER Metal2 ;
        RECT 152.920 78.980 153.320 79.380 ;
    END
  END S4END[12]
  PIN S4END[13]
    DIRECTION INPUT ;
    USE SIGNAL ;
    ANTENNAGATEAREA 0.852800 ;
    PORT
      LAYER Metal2 ;
        RECT 153.880 78.980 154.280 79.380 ;
    END
  END S4END[13]
  PIN S4END[14]
    DIRECTION INPUT ;
    USE SIGNAL ;
    ANTENNAGATEAREA 0.852800 ;
    PORT
      LAYER Metal2 ;
        RECT 154.840 78.980 155.240 79.380 ;
    END
  END S4END[14]
  PIN S4END[15]
    DIRECTION INPUT ;
    USE SIGNAL ;
    ANTENNAGATEAREA 0.852800 ;
    PORT
      LAYER Metal2 ;
        RECT 155.800 78.980 156.200 79.380 ;
    END
  END S4END[15]
  PIN S4END[1]
    DIRECTION INPUT ;
    USE SIGNAL ;
    ANTENNAGATEAREA 0.426400 ;
    PORT
      LAYER Metal2 ;
        RECT 142.360 78.980 142.760 79.380 ;
    END
  END S4END[1]
  PIN S4END[2]
    DIRECTION INPUT ;
    USE SIGNAL ;
    ANTENNAGATEAREA 0.426400 ;
    PORT
      LAYER Metal2 ;
        RECT 143.320 78.980 143.720 79.380 ;
    END
  END S4END[2]
  PIN S4END[3]
    DIRECTION INPUT ;
    USE SIGNAL ;
    ANTENNAGATEAREA 0.426400 ;
    ANTENNADIFFAREA 8.061600 ;
    PORT
      LAYER Metal2 ;
        RECT 144.280 78.980 144.680 79.380 ;
    END
  END S4END[3]
  PIN S4END[4]
    DIRECTION INPUT ;
    USE SIGNAL ;
    ANTENNAGATEAREA 0.639600 ;
    PORT
      LAYER Metal2 ;
        RECT 145.240 78.980 145.640 79.380 ;
    END
  END S4END[4]
  PIN S4END[5]
    DIRECTION INPUT ;
    USE SIGNAL ;
    ANTENNAGATEAREA 0.426400 ;
    PORT
      LAYER Metal2 ;
        RECT 146.200 78.980 146.600 79.380 ;
    END
  END S4END[5]
  PIN S4END[6]
    DIRECTION INPUT ;
    USE SIGNAL ;
    ANTENNAGATEAREA 0.426400 ;
    PORT
      LAYER Metal2 ;
        RECT 147.160 78.980 147.560 79.380 ;
    END
  END S4END[6]
  PIN S4END[7]
    DIRECTION INPUT ;
    USE SIGNAL ;
    ANTENNAGATEAREA 0.426400 ;
    PORT
      LAYER Metal2 ;
        RECT 148.120 78.980 148.520 79.380 ;
    END
  END S4END[7]
  PIN S4END[8]
    DIRECTION INPUT ;
    USE SIGNAL ;
    ANTENNAGATEAREA 0.639600 ;
    PORT
      LAYER Metal2 ;
        RECT 149.080 78.980 149.480 79.380 ;
    END
  END S4END[8]
  PIN S4END[9]
    DIRECTION INPUT ;
    USE SIGNAL ;
    ANTENNAGATEAREA 0.639600 ;
    PORT
      LAYER Metal2 ;
        RECT 150.040 78.980 150.440 79.380 ;
    END
  END S4END[9]
  PIN SLOT_SOFT_RST_N
    DIRECTION INPUT ;
    USE SIGNAL ;
    ANTENNAGATEAREA 0.443300 ;
    PORT
      LAYER Metal2 ;
        RECT 175.000 0.000 175.400 0.400 ;
    END
  END SLOT_SOFT_RST_N
  PIN SS4END[0]
    DIRECTION INPUT ;
    USE SIGNAL ;
    ANTENNAGATEAREA 0.426400 ;
    PORT
      LAYER Metal2 ;
        RECT 171.160 78.980 171.560 79.380 ;
    END
  END SS4END[0]
  PIN SS4END[10]
    DIRECTION INPUT ;
    USE SIGNAL ;
    ANTENNAGATEAREA 0.639600 ;
    PORT
      LAYER Metal2 ;
        RECT 180.760 78.980 181.160 79.380 ;
    END
  END SS4END[10]
  PIN SS4END[11]
    DIRECTION INPUT ;
    USE SIGNAL ;
    ANTENNAGATEAREA 0.639600 ;
    PORT
      LAYER Metal2 ;
        RECT 181.720 78.980 182.120 79.380 ;
    END
  END SS4END[11]
  PIN SS4END[12]
    DIRECTION INPUT ;
    USE SIGNAL ;
    ANTENNAGATEAREA 0.852800 ;
    PORT
      LAYER Metal2 ;
        RECT 182.680 78.980 183.080 79.380 ;
    END
  END SS4END[12]
  PIN SS4END[13]
    DIRECTION INPUT ;
    USE SIGNAL ;
    ANTENNAGATEAREA 0.852800 ;
    PORT
      LAYER Metal2 ;
        RECT 183.640 78.980 184.040 79.380 ;
    END
  END SS4END[13]
  PIN SS4END[14]
    DIRECTION INPUT ;
    USE SIGNAL ;
    ANTENNAGATEAREA 0.852800 ;
    PORT
      LAYER Metal2 ;
        RECT 184.600 78.980 185.000 79.380 ;
    END
  END SS4END[14]
  PIN SS4END[15]
    DIRECTION INPUT ;
    USE SIGNAL ;
    ANTENNAGATEAREA 0.852800 ;
    PORT
      LAYER Metal2 ;
        RECT 185.560 78.980 185.960 79.380 ;
    END
  END SS4END[15]
  PIN SS4END[1]
    DIRECTION INPUT ;
    USE SIGNAL ;
    ANTENNAGATEAREA 0.426400 ;
    PORT
      LAYER Metal2 ;
        RECT 172.120 78.980 172.520 79.380 ;
    END
  END SS4END[1]
  PIN SS4END[2]
    DIRECTION INPUT ;
    USE SIGNAL ;
    ANTENNAGATEAREA 0.426400 ;
    PORT
      LAYER Metal2 ;
        RECT 173.080 78.980 173.480 79.380 ;
    END
  END SS4END[2]
  PIN SS4END[3]
    DIRECTION INPUT ;
    USE SIGNAL ;
    ANTENNAGATEAREA 0.426400 ;
    ANTENNADIFFAREA 8.061600 ;
    PORT
      LAYER Metal2 ;
        RECT 174.040 78.980 174.440 79.380 ;
    END
  END SS4END[3]
  PIN SS4END[4]
    DIRECTION INPUT ;
    USE SIGNAL ;
    ANTENNAGATEAREA 0.639600 ;
    PORT
      LAYER Metal2 ;
        RECT 175.000 78.980 175.400 79.380 ;
    END
  END SS4END[4]
  PIN SS4END[5]
    DIRECTION INPUT ;
    USE SIGNAL ;
    ANTENNAGATEAREA 0.426400 ;
    PORT
      LAYER Metal2 ;
        RECT 175.960 78.980 176.360 79.380 ;
    END
  END SS4END[5]
  PIN SS4END[6]
    DIRECTION INPUT ;
    USE SIGNAL ;
    ANTENNAGATEAREA 0.426400 ;
    PORT
      LAYER Metal2 ;
        RECT 176.920 78.980 177.320 79.380 ;
    END
  END SS4END[6]
  PIN SS4END[7]
    DIRECTION INPUT ;
    USE SIGNAL ;
    ANTENNAGATEAREA 0.426400 ;
    PORT
      LAYER Metal2 ;
        RECT 177.880 78.980 178.280 79.380 ;
    END
  END SS4END[7]
  PIN SS4END[8]
    DIRECTION INPUT ;
    USE SIGNAL ;
    ANTENNAGATEAREA 0.639600 ;
    PORT
      LAYER Metal2 ;
        RECT 178.840 78.980 179.240 79.380 ;
    END
  END SS4END[8]
  PIN SS4END[9]
    DIRECTION INPUT ;
    USE SIGNAL ;
    ANTENNAGATEAREA 0.639600 ;
    PORT
      LAYER Metal2 ;
        RECT 179.800 78.980 180.200 79.380 ;
    END
  END SS4END[9]
  PIN USR_IRQ
    DIRECTION OUTPUT ;
    USE SIGNAL ;
    ANTENNADIFFAREA 3.023500 ;
    PORT
      LAYER Metal2 ;
        RECT 226.840 0.000 227.240 0.400 ;
    END
  END USR_IRQ
  PIN UserCLK
    DIRECTION INPUT ;
    USE SIGNAL ;
    ANTENNAGATEAREA 1.450800 ;
    PORT
      LAYER Metal3 ;
        RECT 0.000 1.900 0.400 2.300 ;
    END
  END UserCLK
  PIN UserCLKo
    DIRECTION OUTPUT ;
    USE SIGNAL ;
    ANTENNADIFFAREA 2.724000 ;
    PORT
      LAYER Metal3 ;
        RECT 232.880 1.900 233.280 2.300 ;
    END
  END UserCLKo
  PIN VGND
    DIRECTION INOUT ;
    USE GROUND ;
    PORT
      LAYER Metal4 ;
        RECT 15.380 0.000 16.380 79.380 ;
    END
    PORT
      LAYER Metal4 ;
        RECT 65.380 0.000 66.380 79.380 ;
    END
    PORT
      LAYER Metal4 ;
        RECT 115.380 0.000 116.380 79.380 ;
    END
    PORT
      LAYER Metal4 ;
        RECT 165.380 0.000 166.380 79.380 ;
    END
    PORT
      LAYER Metal4 ;
        RECT 215.380 0.000 216.380 79.380 ;
    END
  END VGND
  PIN VPWR
    DIRECTION INOUT ;
    USE POWER ;
    PORT
      LAYER Metal4 ;
        RECT 12.380 0.000 13.380 79.380 ;
    END
    PORT
      LAYER Metal4 ;
        RECT 62.380 0.000 63.380 79.380 ;
    END
    PORT
      LAYER Metal4 ;
        RECT 112.380 0.000 113.380 79.380 ;
    END
    PORT
      LAYER Metal4 ;
        RECT 162.380 0.000 163.380 79.380 ;
    END
    PORT
      LAYER Metal4 ;
        RECT 212.380 0.000 213.380 79.380 ;
    END
  END VPWR
  OBS
      LAYER GatPoly ;
        RECT 2.880 3.630 230.400 75.750 ;
      LAYER Metal1 ;
        RECT 2.880 3.560 230.400 75.820 ;
      LAYER Metal2 ;
        RECT 0.375 78.770 1.030 79.105 ;
        RECT 1.850 78.770 2.950 79.105 ;
        RECT 3.770 78.770 4.870 79.105 ;
        RECT 5.690 78.770 6.790 79.105 ;
        RECT 7.610 78.770 11.590 79.105 ;
        RECT 12.410 78.770 12.550 79.105 ;
        RECT 13.370 78.770 13.510 79.105 ;
        RECT 14.330 78.770 14.470 79.105 ;
        RECT 15.290 78.770 15.430 79.105 ;
        RECT 16.250 78.770 16.390 79.105 ;
        RECT 17.210 78.770 17.350 79.105 ;
        RECT 18.170 78.770 18.310 79.105 ;
        RECT 19.130 78.770 25.990 79.105 ;
        RECT 26.810 78.770 26.950 79.105 ;
        RECT 27.770 78.770 27.910 79.105 ;
        RECT 28.730 78.770 28.870 79.105 ;
        RECT 29.690 78.770 29.830 79.105 ;
        RECT 30.650 78.770 30.790 79.105 ;
        RECT 31.610 78.770 31.750 79.105 ;
        RECT 32.570 78.770 32.710 79.105 ;
        RECT 33.530 78.770 44.230 79.105 ;
        RECT 45.050 78.770 45.190 79.105 ;
        RECT 46.010 78.770 46.150 79.105 ;
        RECT 46.970 78.770 47.110 79.105 ;
        RECT 47.930 78.770 48.070 79.105 ;
        RECT 48.890 78.770 49.030 79.105 ;
        RECT 49.850 78.770 49.990 79.105 ;
        RECT 50.810 78.770 50.950 79.105 ;
        RECT 51.770 78.770 51.910 79.105 ;
        RECT 52.730 78.770 52.870 79.105 ;
        RECT 53.690 78.770 53.830 79.105 ;
        RECT 54.650 78.770 54.790 79.105 ;
        RECT 55.610 78.770 55.750 79.105 ;
        RECT 56.570 78.770 56.710 79.105 ;
        RECT 57.530 78.770 57.670 79.105 ;
        RECT 58.490 78.770 58.630 79.105 ;
        RECT 59.450 78.770 73.990 79.105 ;
        RECT 74.810 78.770 74.950 79.105 ;
        RECT 75.770 78.770 75.910 79.105 ;
        RECT 76.730 78.770 76.870 79.105 ;
        RECT 77.690 78.770 77.830 79.105 ;
        RECT 78.650 78.770 78.790 79.105 ;
        RECT 79.610 78.770 79.750 79.105 ;
        RECT 80.570 78.770 80.710 79.105 ;
        RECT 81.530 78.770 81.670 79.105 ;
        RECT 82.490 78.770 82.630 79.105 ;
        RECT 83.450 78.770 83.590 79.105 ;
        RECT 84.410 78.770 84.550 79.105 ;
        RECT 85.370 78.770 85.510 79.105 ;
        RECT 86.330 78.770 86.470 79.105 ;
        RECT 87.290 78.770 87.430 79.105 ;
        RECT 88.250 78.770 88.390 79.105 ;
        RECT 89.210 78.770 97.030 79.105 ;
        RECT 97.850 78.770 98.950 79.105 ;
        RECT 99.770 78.770 100.870 79.105 ;
        RECT 101.690 78.770 102.790 79.105 ;
        RECT 103.610 78.770 104.710 79.105 ;
        RECT 105.530 78.770 106.630 79.105 ;
        RECT 107.450 78.770 108.550 79.105 ;
        RECT 109.370 78.770 110.470 79.105 ;
        RECT 111.290 78.770 112.390 79.105 ;
        RECT 113.210 78.770 114.310 79.105 ;
        RECT 115.130 78.770 116.230 79.105 ;
        RECT 117.050 78.770 118.150 79.105 ;
        RECT 118.970 78.770 122.950 79.105 ;
        RECT 123.770 78.770 123.910 79.105 ;
        RECT 124.730 78.770 124.870 79.105 ;
        RECT 125.690 78.770 125.830 79.105 ;
        RECT 126.650 78.770 126.790 79.105 ;
        RECT 127.610 78.770 127.750 79.105 ;
        RECT 128.570 78.770 128.710 79.105 ;
        RECT 129.530 78.770 129.670 79.105 ;
        RECT 130.490 78.770 141.190 79.105 ;
        RECT 142.010 78.770 142.150 79.105 ;
        RECT 142.970 78.770 143.110 79.105 ;
        RECT 143.930 78.770 144.070 79.105 ;
        RECT 144.890 78.770 145.030 79.105 ;
        RECT 145.850 78.770 145.990 79.105 ;
        RECT 146.810 78.770 146.950 79.105 ;
        RECT 147.770 78.770 147.910 79.105 ;
        RECT 148.730 78.770 148.870 79.105 ;
        RECT 149.690 78.770 149.830 79.105 ;
        RECT 150.650 78.770 150.790 79.105 ;
        RECT 151.610 78.770 151.750 79.105 ;
        RECT 152.570 78.770 152.710 79.105 ;
        RECT 153.530 78.770 153.670 79.105 ;
        RECT 154.490 78.770 154.630 79.105 ;
        RECT 155.450 78.770 155.590 79.105 ;
        RECT 156.410 78.770 170.950 79.105 ;
        RECT 171.770 78.770 171.910 79.105 ;
        RECT 172.730 78.770 172.870 79.105 ;
        RECT 173.690 78.770 173.830 79.105 ;
        RECT 174.650 78.770 174.790 79.105 ;
        RECT 175.610 78.770 175.750 79.105 ;
        RECT 176.570 78.770 176.710 79.105 ;
        RECT 177.530 78.770 177.670 79.105 ;
        RECT 178.490 78.770 178.630 79.105 ;
        RECT 179.450 78.770 179.590 79.105 ;
        RECT 180.410 78.770 180.550 79.105 ;
        RECT 181.370 78.770 181.510 79.105 ;
        RECT 182.330 78.770 182.470 79.105 ;
        RECT 183.290 78.770 183.430 79.105 ;
        RECT 184.250 78.770 184.390 79.105 ;
        RECT 185.210 78.770 185.350 79.105 ;
        RECT 186.170 78.770 193.990 79.105 ;
        RECT 194.810 78.770 204.550 79.105 ;
        RECT 205.370 78.770 205.510 79.105 ;
        RECT 206.330 78.770 206.470 79.105 ;
        RECT 207.290 78.770 207.430 79.105 ;
        RECT 208.250 78.770 208.390 79.105 ;
        RECT 209.210 78.770 209.350 79.105 ;
        RECT 210.170 78.770 210.310 79.105 ;
        RECT 211.130 78.770 211.270 79.105 ;
        RECT 212.090 78.770 212.230 79.105 ;
        RECT 213.050 78.770 213.190 79.105 ;
        RECT 214.010 78.770 214.150 79.105 ;
        RECT 214.970 78.770 215.110 79.105 ;
        RECT 215.930 78.770 216.070 79.105 ;
        RECT 216.890 78.770 217.030 79.105 ;
        RECT 217.850 78.770 217.990 79.105 ;
        RECT 218.810 78.770 218.950 79.105 ;
        RECT 219.770 78.770 219.910 79.105 ;
        RECT 220.730 78.770 220.870 79.105 ;
        RECT 221.690 78.770 221.830 79.105 ;
        RECT 222.650 78.770 222.790 79.105 ;
        RECT 223.610 78.770 229.065 79.105 ;
        RECT 0.375 0.610 229.065 78.770 ;
        RECT 0.375 0.320 6.790 0.610 ;
        RECT 7.610 0.320 12.550 0.610 ;
        RECT 13.370 0.320 18.310 0.610 ;
        RECT 19.130 0.320 24.070 0.610 ;
        RECT 24.890 0.320 29.830 0.610 ;
        RECT 30.650 0.320 35.590 0.610 ;
        RECT 36.410 0.320 41.350 0.610 ;
        RECT 42.170 0.320 47.110 0.610 ;
        RECT 47.930 0.320 52.870 0.610 ;
        RECT 53.690 0.320 58.630 0.610 ;
        RECT 59.450 0.320 64.390 0.610 ;
        RECT 65.210 0.320 70.150 0.610 ;
        RECT 70.970 0.320 75.910 0.610 ;
        RECT 76.730 0.320 81.670 0.610 ;
        RECT 82.490 0.320 87.430 0.610 ;
        RECT 88.250 0.320 93.190 0.610 ;
        RECT 94.010 0.320 98.950 0.610 ;
        RECT 99.770 0.320 104.710 0.610 ;
        RECT 105.530 0.320 110.470 0.610 ;
        RECT 111.290 0.320 116.230 0.610 ;
        RECT 117.050 0.320 128.710 0.610 ;
        RECT 129.530 0.320 134.470 0.610 ;
        RECT 135.290 0.320 140.230 0.610 ;
        RECT 141.050 0.320 145.990 0.610 ;
        RECT 146.810 0.320 151.750 0.610 ;
        RECT 152.570 0.320 157.510 0.610 ;
        RECT 158.330 0.320 163.270 0.610 ;
        RECT 164.090 0.320 169.030 0.610 ;
        RECT 169.850 0.320 174.790 0.610 ;
        RECT 175.610 0.320 180.550 0.610 ;
        RECT 181.370 0.320 186.310 0.610 ;
        RECT 187.130 0.320 192.070 0.610 ;
        RECT 192.890 0.320 197.830 0.610 ;
        RECT 198.650 0.320 203.590 0.610 ;
        RECT 204.410 0.320 209.350 0.610 ;
        RECT 210.170 0.320 215.110 0.610 ;
        RECT 215.930 0.320 220.870 0.610 ;
        RECT 221.690 0.320 226.630 0.610 ;
        RECT 227.450 0.320 229.065 0.610 ;
      LAYER Metal3 ;
        RECT 0.335 68.030 232.880 79.065 ;
        RECT 0.610 67.210 232.670 68.030 ;
        RECT 0.335 66.350 232.880 67.210 ;
        RECT 0.610 65.530 232.670 66.350 ;
        RECT 0.335 64.670 232.880 65.530 ;
        RECT 0.610 63.850 232.670 64.670 ;
        RECT 0.335 62.990 232.880 63.850 ;
        RECT 0.610 62.170 232.670 62.990 ;
        RECT 0.335 61.310 232.880 62.170 ;
        RECT 0.610 60.490 232.670 61.310 ;
        RECT 0.335 59.630 232.880 60.490 ;
        RECT 0.610 58.810 232.670 59.630 ;
        RECT 0.335 57.950 232.880 58.810 ;
        RECT 0.610 57.130 232.670 57.950 ;
        RECT 0.335 56.270 232.880 57.130 ;
        RECT 0.610 55.450 232.670 56.270 ;
        RECT 0.335 54.590 232.880 55.450 ;
        RECT 0.610 53.770 232.670 54.590 ;
        RECT 0.335 52.910 232.880 53.770 ;
        RECT 0.610 52.090 232.670 52.910 ;
        RECT 0.335 51.230 232.880 52.090 ;
        RECT 0.610 50.410 232.670 51.230 ;
        RECT 0.335 49.550 232.880 50.410 ;
        RECT 0.610 48.730 232.670 49.550 ;
        RECT 0.335 47.870 232.880 48.730 ;
        RECT 0.610 47.050 232.670 47.870 ;
        RECT 0.335 46.190 232.880 47.050 ;
        RECT 0.610 45.370 232.670 46.190 ;
        RECT 0.335 44.510 232.880 45.370 ;
        RECT 0.610 43.690 232.670 44.510 ;
        RECT 0.335 42.830 232.880 43.690 ;
        RECT 0.610 42.010 232.670 42.830 ;
        RECT 0.335 41.150 232.880 42.010 ;
        RECT 0.610 40.330 232.670 41.150 ;
        RECT 0.335 39.470 232.880 40.330 ;
        RECT 0.610 38.650 232.670 39.470 ;
        RECT 0.335 37.790 232.880 38.650 ;
        RECT 0.610 36.970 232.670 37.790 ;
        RECT 0.335 36.110 232.880 36.970 ;
        RECT 0.610 35.290 232.670 36.110 ;
        RECT 0.335 34.430 232.880 35.290 ;
        RECT 0.610 33.610 232.670 34.430 ;
        RECT 0.335 32.750 232.880 33.610 ;
        RECT 0.610 31.930 232.670 32.750 ;
        RECT 0.335 31.070 232.880 31.930 ;
        RECT 0.610 30.250 232.670 31.070 ;
        RECT 0.335 29.390 232.880 30.250 ;
        RECT 0.610 28.570 232.670 29.390 ;
        RECT 0.335 27.710 232.880 28.570 ;
        RECT 0.610 26.890 232.670 27.710 ;
        RECT 0.335 26.030 232.880 26.890 ;
        RECT 0.610 25.210 232.670 26.030 ;
        RECT 0.335 24.350 232.880 25.210 ;
        RECT 0.610 23.530 232.670 24.350 ;
        RECT 0.335 22.670 232.880 23.530 ;
        RECT 0.610 21.850 232.670 22.670 ;
        RECT 0.335 20.990 232.880 21.850 ;
        RECT 0.610 20.170 232.670 20.990 ;
        RECT 0.335 19.310 232.880 20.170 ;
        RECT 0.610 18.490 232.670 19.310 ;
        RECT 0.335 17.630 232.880 18.490 ;
        RECT 0.610 16.810 232.670 17.630 ;
        RECT 0.335 15.950 232.880 16.810 ;
        RECT 0.610 15.130 232.670 15.950 ;
        RECT 0.335 2.510 232.880 15.130 ;
        RECT 0.610 1.690 232.670 2.510 ;
        RECT 0.335 1.160 232.880 1.690 ;
      LAYER Metal4 ;
        RECT 10.460 1.955 12.170 79.105 ;
        RECT 13.590 1.955 15.170 79.105 ;
        RECT 16.590 1.955 62.170 79.105 ;
        RECT 63.590 1.955 65.170 79.105 ;
        RECT 66.590 1.955 112.170 79.105 ;
        RECT 113.590 1.955 115.170 79.105 ;
        RECT 116.590 1.955 162.170 79.105 ;
        RECT 163.590 1.955 165.170 79.105 ;
        RECT 166.590 1.955 212.170 79.105 ;
        RECT 213.590 1.955 215.170 79.105 ;
        RECT 216.590 1.955 223.780 79.105 ;
      LAYER TopMetal1 ;
        RECT 27.980 5.380 209.620 75.420 ;
  END
END SOC_DEBUG_IO
END LIBRARY

